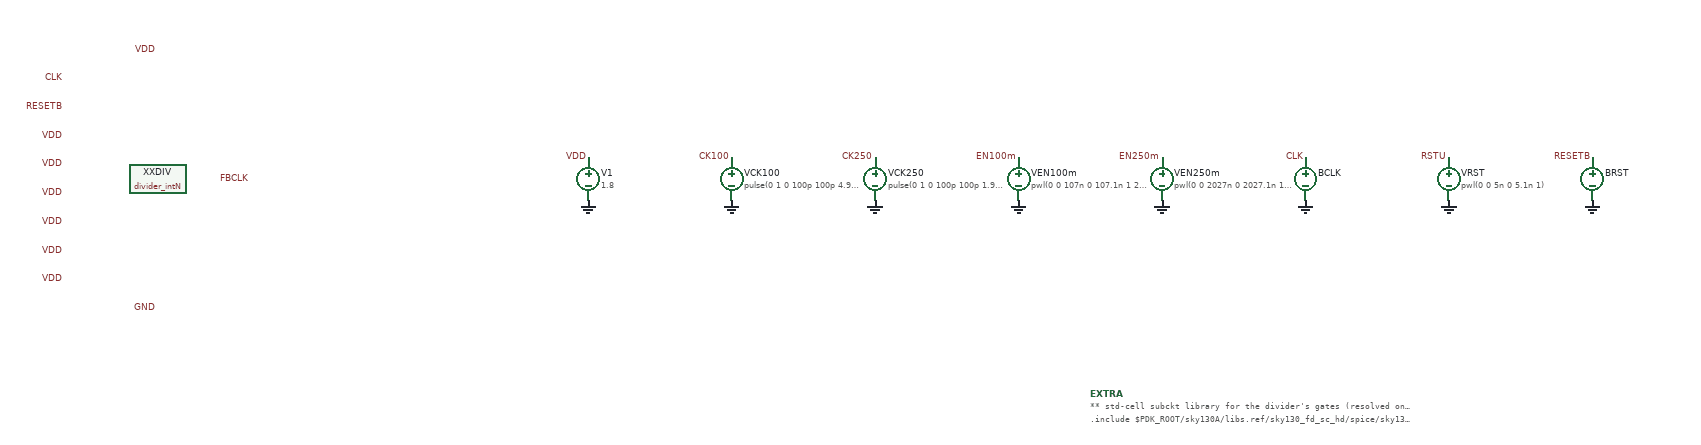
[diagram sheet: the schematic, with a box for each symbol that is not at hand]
v {xschem version=3.4.7 file_version=1.2
* tb_power_divider_n64.sch -- sky130 divider_intN supply-current campaign, N=64 (issue #233)
* GENERATED by sim/power/build.py from its stage table; do not hand-edit.
*
* design/divider/divider_intN.sch configured N=64 (NSEL=63); the input clock is an ideal rail-to-rail source gated per stage; FBCLK is unloaded.
*
* V1 is the ONLY supply source on the DUT's VDD net, so i(V1) is the block's
* own supply current. The stimulus (staged sources, idle stage first) is the
* drawn stimulus sources; sim/power/testbench/divider-n64.stages.json is the
* machine-readable stage table the reducer uses.
*
* Provenance: adapted from sim/vco-supply-pushing/testbench/tb_vco_pushing.sch
* (this repo, issue #165): same label-pin wiring, V1 supply, DUT instance style.
}
G {}
V {}
S {}
E {}

C {design/divider/divider_intN.sym} 0 0 0 0 {name=XXDIV}
C {devices/lab_pin.sym} 0 -180 0 0 {name=p1 sig_type=std_logic lab=VDD}
C {devices/lab_pin.sym} 0 180 0 0 {name=p2 sig_type=std_logic lab=GND}
C {devices/lab_pin.sym} -130 -140 0 0 {name=p3 sig_type=std_logic lab=CLK}
C {devices/lab_pin.sym} -130 -100 0 0 {name=p4 sig_type=std_logic lab=RESETB}
C {devices/lab_pin.sym} -130 -60 0 0 {name=p5 sig_type=std_logic lab=VDD}
C {devices/lab_pin.sym} -130 -20 0 0 {name=p6 sig_type=std_logic lab=VDD}
C {devices/lab_pin.sym} -130 20 0 0 {name=p7 sig_type=std_logic lab=VDD}
C {devices/lab_pin.sym} -130 60 0 0 {name=p8 sig_type=std_logic lab=VDD}
C {devices/lab_pin.sym} -130 100 0 0 {name=p9 sig_type=std_logic lab=VDD}
C {devices/lab_pin.sym} -130 140 0 0 {name=p10 sig_type=std_logic lab=VDD}
C {devices/lab_pin.sym} 130 0 0 0 {name=p11 sig_type=std_logic lab=FBCLK}
C {devices/vsource.sym} 600 0 0 0 {name=V1 value=1.8 savecurrent=false}
C {devices/lab_pin.sym} 600 -30 0 0 {name=pv1 sig_type=std_logic lab=VDD}
C {devices/gnd.sym} 600 30 0 0 {name=lg1 lab=GND}
C {devices/vsource.sym} 800 0 0 0 {name=VCK100 value="pulse(0 1 0 100p 100p 4.9n 10n)" savecurrent=false}
C {devices/lab_pin.sym} 800 -30 0 0 {name=ps1 sig_type=std_logic lab=CK100}
C {devices/gnd.sym} 800 30 0 0 {name=lgs1 lab=GND}
C {devices/vsource.sym} 1000 0 0 0 {name=VCK250 value="pulse(0 1 0 100p 100p 1.9n 4n)" savecurrent=false}
C {devices/lab_pin.sym} 1000 -30 0 0 {name=ps2 sig_type=std_logic lab=CK250}
C {devices/gnd.sym} 1000 30 0 0 {name=lgs2 lab=GND}
C {devices/vsource.sym} 1200 0 0 0 {name=VEN100m value="pwl(0 0 107n 0 107.1n 1 2027n 1 2027.1n 0)" savecurrent=false}
C {devices/lab_pin.sym} 1200 -30 0 0 {name=ps3 sig_type=std_logic lab=EN100m}
C {devices/gnd.sym} 1200 30 0 0 {name=lgs3 lab=GND}
C {devices/vsource.sym} 1400 0 0 0 {name=VEN250m value="pwl(0 0 2027n 0 2027.1n 1 2807n 1 2807.1n 0)" savecurrent=false}
C {devices/lab_pin.sym} 1400 -30 0 0 {name=ps4 sig_type=std_logic lab=EN250m}
C {devices/gnd.sym} 1400 30 0 0 {name=lgs4 lab=GND}
C {devices/bsource.sym} 1600 0 0 0 {name=BCLK VAR=V FUNC="v(VDD)*(v(CK100)*v(EN100m)+v(CK250)*v(EN250m))" m=1}
C {devices/lab_pin.sym} 1600 -30 0 0 {name=ps5 sig_type=std_logic lab=CLK}
C {devices/gnd.sym} 1600 30 0 0 {name=lgs5 lab=GND}
C {devices/vsource.sym} 1800 0 0 0 {name=VRST value="pwl(0 0 5n 0 5.1n 1)" savecurrent=false}
C {devices/lab_pin.sym} 1800 -30 0 0 {name=ps6 sig_type=std_logic lab=RSTU}
C {devices/gnd.sym} 1800 30 0 0 {name=lgs6 lab=GND}
C {devices/bsource.sym} 2000 0 0 0 {name=BRST VAR=V FUNC="v(VDD)*v(RSTU)" m=1}
C {devices/lab_pin.sym} 2000 -30 0 0 {name=ps7 sig_type=std_logic lab=RESETB}
C {devices/gnd.sym} 2000 30 0 0 {name=lgs7 lab=GND}
C {devices/code.sym} 1300 300 0 0 {name=EXTRA
only_toplevel=true
value="
** std-cell subckt library for the divider's gates (resolved on the executing host)
.include $PDK_ROOT/sky130A/libs.ref/sky130_fd_sc_hd/spice/sky130_fd_sc_hd.spice
"
spice_ignore=false}
C {devices/title.sym} -200 500 0 0 {name=lt author="2AM Logic (issue #233, sky130 divider_intN supply-current campaign, N=64)"}
